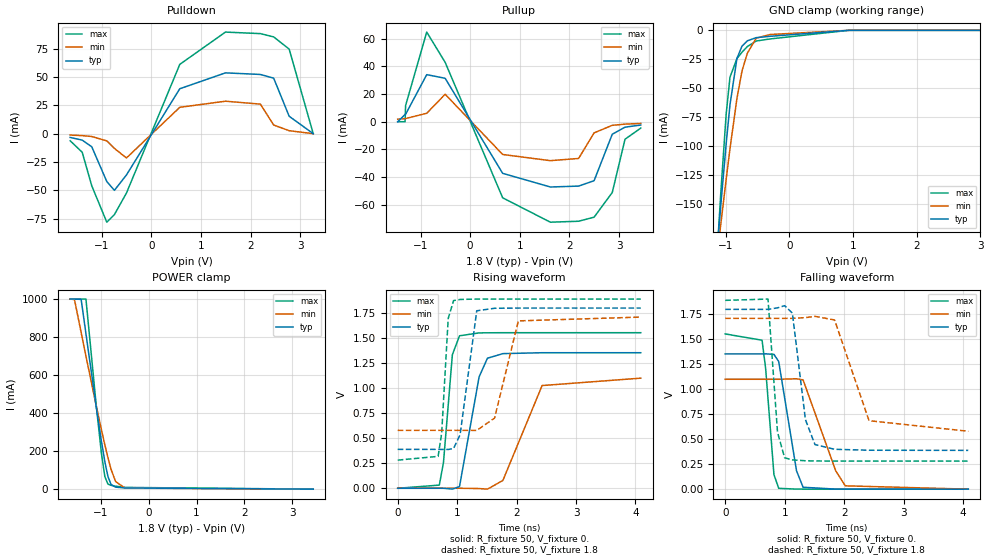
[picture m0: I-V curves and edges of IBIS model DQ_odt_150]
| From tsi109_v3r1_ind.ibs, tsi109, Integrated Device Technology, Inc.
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|   MODEL DQ_odt_150
[Model]   DQ_odt_150
Model_type  I/O
Polarity   Non-Inverting
Enable   Active-Low
|   typ   min   max
|C_comp_off 3.662p 3.671p 3.594p
|C_comp_on 3.698p 3.56p 3.948p
C_comp 3.68p 3.615p 3.771p
Cref  =   20pF
Vmeas =   0.9v
Vinl  =   0.650v
Vinh  =   1.150v
[Model Spec]
[Temperature Range]   25   125   -40
[Voltage Range] 1.8 1.71 1.89
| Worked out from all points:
|   slope of the pulldown table from 0 to 0.27 V, typ, clamps not added: 14.1 ohm
|   slope of the pullup table from 0 to 0.27 V, typ, clamps not added: 16.4 ohm
|   rising waveform, R_fixture 50, V_fixture 0.: 20-80 % time 205ps typ, 380ps min, 124ps max; typ from 0 V to 1.35 V
|   rising waveform, R_fixture 50, V_fixture 1.8: 20-80 % time 121ps typ, 188ps min, 85.6ps max; typ from 0.389 V to 1.8 V
|   falling waveform, R_fixture 50, V_fixture 0.: 20-80 % time 211ps typ, 348ps min, 119ps max; typ from 1.35 V to 0 V
|   falling waveform, R_fixture 50, V_fixture 1.8: 20-80 % time 164ps typ, 316ps min, 100ps max; typ from 1.8 V to 0.389 V
[Pulldown]
-1.636V   -3.323mA   -1.212mA   -6.26mA
-1.394V   -5.682mA   -1.723mA   -16.42mA
-1.201V   -11.61mA   -2.501mA   -46.12mA
-898.6mV  -42.29mA   -6.366mA   -78.23mA
-745.2mV  -50.07mA   -13.02mA   -71.52mA
-502.6mV  -36.5mA    -21.48mA   -52.49mA
571.6mV   39.71mA    23.3mA     61.25mA
1.492V    53.75mA    28.7mA     89.79mA
2.195V    52.34mA    26.13mA    88.44mA
2.463V    49.07mA    7.654mA    85.53mA
2.775V    15.41mA    2.629mA    74.76mA
3.26V     0A         0A         0A
[Pullup]
-1.46V    0A         1.84mA     0A
-1.311V   5.209mA    2.254mA    0A
-1.301V   5.351mA    2.288mA    11.67mA
-875.5mV  33.99mA    6.09mA     64.72mA
-504.2mV  31.36mA    19.84mA    42.89mA
654.2mV   -37.26mA   -23.65mA   -54.93mA
1.615V    -47.13mA   -28.11mA   -72.54mA
2.184V    -46.48mA   -26.52mA   -71.86mA
2.496V    -42.58mA   -8.056mA   -68.92mA
2.862V    -9.049mA   -2.593mA   -51.09mA
3.119V    -3.923mA   -1.743mA   -12.65mA
3.436V    -2.406mA   -1.258mA   -4.596mA
[GND Clamp]
-1.636V   -544mA     -441.4mA   -698.5mA
-1.119V   -177.5mA   -186.1mA   -176.8mA
-1.079V   -151.2mA   -167.4mA   -140.5mA
-994.2mV  -97.84mA   -128.5mA   -72.19mA
-934.4mV  -64.27mA   -102.2mA   -40.44mA
-824.9mV  -24.2mA    -58.74mA   -24.37mA
-745.3mV  -13.62mA   -34.97mA   -18.86mA
-660.7mV  -9.028mA   -19.65mA   -13.95mA
-521.3mV  -6.307mA   -6.754mA   -9.213mA
-307.3mV  -5.162mA   -3.62mA    -7.441mA
931.9mV   0A         0A         0A
3.26V     0A         0A         0A
[Power Clamp]
-1.636V   1A         1A         1A
-1.546V   1A         997.3mA    1A
-1.407V   998.2mA    823.6mA    1A
-1.307V   817.6mA    699.9mA    1A
-1.088V   425.2mA    433.6mA    429.7mA
-982.8mV  250.1mA    311.6mA    185.6mA
-913mV    144.8mA    233.7mA    66.39mA
-848.2mV  66.74mA    165.6mA    26.56mA
-783.3mV  24.69mA    104.6mA    20.16mA
-688.6mV  10.68mA    40.26mA    15.6mA
-494mV    6.246mA    5.746mA    9.256mA
3.436V    0A         0A         0A
[Ramp]
dV/dt_r .812/205.375p .66/380.602p .932/123.936p
dV/dt_f .847/163.938p .679/315.888p .965/99.968p
[Rising Waveform]
R_fixture = 50
V_fixture = 0.
0s        0V         0V         0V
700ps     244.5uV    -2.152uV   31.55mV
770ps     49.9uV     875.3nV    255.6mV
920ps     -8.207mV   73.82uV    1.334V
1.04ns    16.71mV    185.6uV    1.523V
1.37ns    1.113V     -2.911mV   1.552V
1.51ns    1.299V     -9.011mV   1.553V
1.77ns    1.345V     78.26mV    1.554V
2.43ns    1.354V     1.026V     1.554V
4.09ns    1.354V     1.1V       1.554V
[Rising Waveform]
R_fixture = 50
V_fixture = 1.8
V_fixture_min = 1.71
V_fixture_max = 1.89
0s        388.5mV    578.6mV    281mV
680ps     388.4mV    578.7mV    318.7mV
740ps     388mV      578.7mV    550.7mV
850ps     387.5mV    578.7mV    1.696V
940ps     397.2mV    578.7mV    1.875V
1.05ns    535.1mV    578.4mV    1.886V
1.33ns    1.773V     577.6mV    1.89V
1.63ns    1.798V     701.1mV    1.89V
2.03ns    1.8V       1.672V     1.89V
4.09ns    1.8V       1.71V      1.89V
[Falling Waveform]
R_fixture = 50
V_fixture = 0.
0s        1.354V     1.1V       1.554V
620ps     1.354V     1.1V       1.491V
680ps     1.355V     1.1V       1.208V
820ps     1.349V     1.1V       145.9mV
900ps     1.278V     1.1V       8.41mV
1.2ns     183.3mV    1.105V     710uV
1.31ns    19.37mV    1.094V     400.2uV
1.86ns    480.7uV    183.1mV    21.03uV
2.02ns    258.4uV    33.45mV    9.172uV
4.09ns    0V         23.14uV    0V
[Falling Waveform]
R_fixture = 50
V_fixture = 1.8
V_fixture_min = 1.71
V_fixture_max = 1.89
0s        1.8V       1.71V      1.89V
720ps     1.8V       1.71V      1.903V
880ps     1.815V     1.71V      568.6mV
1ns       1.837V     1.71V      313.4mV
1.13ns    1.762V     1.71V      293.2mV
1.35ns    695.3mV    1.717V     284.2mV
1.51ns    446.5mV    1.73V      282.3mV
1.84ns    399.2mV    1.694V     281.2mV
2.42ns    389.6mV    685.4mV    281mV
4.09ns    388.5mV    579.6mV    281mV
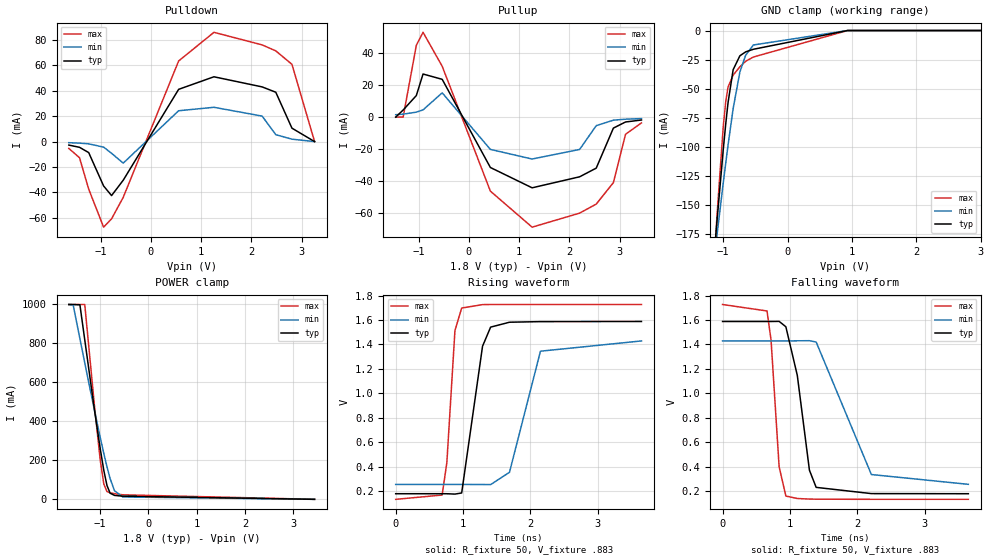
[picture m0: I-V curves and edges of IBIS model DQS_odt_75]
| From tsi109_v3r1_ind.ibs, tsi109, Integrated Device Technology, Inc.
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|   MODEL DQS_odt_75
[Model]   DQS_odt_75
Model_type  I/O
Polarity   Non-Inverting
Enable   Active-Low
|   typ   min   max
|C_comp_off 3.406p 3.404p 3.36p
|C_comp_on 3.3p 3.146p 3.514p
C_comp 3.353p 3.275p 3.437p
Cref  =   20pF
Vmeas =   0.9v
Vinl  =   0.650v
Vinh  =   1.150v
[Model Spec]
[Temperature Range]   25   125   -40
[Voltage Range] 1.8 1.71 1.89
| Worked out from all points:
|   slope of the pulldown table from 0 to 0.27 V, typ, clamps not added: 15.3 ohm
|   slope of the pullup table from 0 to 0.27 V, typ, clamps not added: 18.6 ohm
|   rising waveform, R_fixture 50, V_fixture .883: 20-80 % time 155ps typ, 260ps min, 101ps max; typ from 0.179 V to 1.59 V
|   falling waveform, R_fixture 50, V_fixture .883: 20-80 % time 210ps typ, 436ps min, 109ps max; typ from 1.59 V to 0.179 V
[Pulldown]
-1.636V   -2.749mA   -869.2uA   -5.385mA
-1.423V   -4.505mA   -1.22mA    -12.72mA
-1.24V    -8.674mA   -1.765mA   -37.45mA
-943.1mV  -34.96mA   -4.367mA   -67.46mA
-784.7mV  -42.57mA   -9.214mA   -60.9mA
-552.1mV  -30.44mA   -16.98mA   -43.96mA
551.8mV   41.2mA     24.32mA    63.56mA
1.255V    51.1mA     27.04mA    86.15mA
2.215V    43.12mA    20.1mA     76.25mA
2.487V    38.92mA    5.461mA    71.53mA
2.809V    10.58mA    1.904mA    60.92mA
3.26V     0A         0A         0A
[Pullup]
-1.46V    0A         1.493mA    0A
-1.311V   4.439mA    1.848mA    0A
-1.049V   13.48mA    3.088mA    44.96mA
-915.1mV  26.96mA    4.523mA    53.07mA
-533.9mV  23.65mA    15.18mA    31.84mA
426.4mV   -31.56mA   -20.23mA   -46.37mA
1.258V    -44.28mA   -26.26mA   -68.91mA
2.204V    -37.38mA   -20.25mA   -60.13mA
2.535V    -31.95mA   -5.371mA   -54.47mA
2.877V    -6.877mA   -1.927mA   -41.02mA
3.119V    -3.056mA   -1.316mA   -10.76mA
3.436V    -1.832mA   -944.9uA   -3.634mA
[GND Clamp]
-1.636V   -544.5mA   -441.7mA   -699.3mA
-1.118V   -178.8mA   -186.7mA   -179.7mA
-1.093V   -162.3mA   -174.9mA   -157.3mA
-998.9mV  -102.8mA   -131.4mA   -83.01mA
-959.1mV  -80.05mA   -113.8mA   -60.91mA
-924.2mV  -62.17mA   -98.82mA   -48.74mA
-844.6mV  -33.7mA    -67.13mA   -38.4mA
-740mV    -21.75mA   -35.66mA   -31.2mA
-650.4mV  -18.38mA   -21.25mA   -26.45mA
-530.9mV  -16.15mA   -12.45mA   -22.82mA
932.4mV   0A         0A         0A
3.26V     0A         0A         0A
[Power Clamp]
-1.636V   1A         1A         1A
-1.546V   1A         997.4mA    1A
-1.407V   998.4mA    824mA      1A
-1.307V   818.5mA    700.4mA    1A
-1.108V   461.3mA    458.1mA    482.6mA
-988mV    260.1mA    318.2mA    202.5mA
-913.2mV  147.7mA    234.7mA    77.91mA
-848.4mV  71mA       166.8mA    39.93mA
-783.6mV  31.4mA     106.1mA    33.6mA
-693.8mV  20.28mA    44.56mA    29.16mA
-524.3mV  16.19mA    12.26mA    23.2mA
3.436V    0A         0A         0A
[Ramp]
dV/dt_r .845/154.678p .705/260.261p .956/101.167p
dV/dt_f .845/210.589p .705/436.081p .956/108.694p
[Rising Waveform]
R_fixture = 50
V_fixture = .883
V_fixture_min = .842
V_fixture_max = .93
0s        179.2mV    255.2mV    133.3mV
690ps     179.3mV    255.2mV    168.3mV
760ps     179mV      255.2mV    435.5mV
880ps     176.2mV    255.2mV    1.514V
980ps     185.4mV    255.3mV    1.698V
1.29ns    1.386V     254.4mV    1.726V
1.41ns    1.542V     253.8mV    1.727V
1.69ns    1.582V     354.6mV    1.727V
2.15ns    1.587V     1.345V     1.727V
3.65ns    1.588V     1.429V     1.727V
[Falling Waveform]
R_fixture = 50
V_fixture = .883
V_fixture_min = .842
V_fixture_max = .93
0s        1.588V     1.429V     1.727V
660ps     1.588V     1.429V     1.674V
720ps     1.588V     1.429V     1.437V
840ps     1.589V     1.429V     399.9mV
940ps     1.545V     1.429V     160.3mV
1.11ns    1.147V     1.43V      140mV
1.29ns    371.6mV    1.431V     135.5mV
1.39ns    231.1mV    1.42V      134.5mV
2.21ns    180.2mV    336.1mV    133.3mV
3.65ns    179.2mV    256.1mV    133.3mV
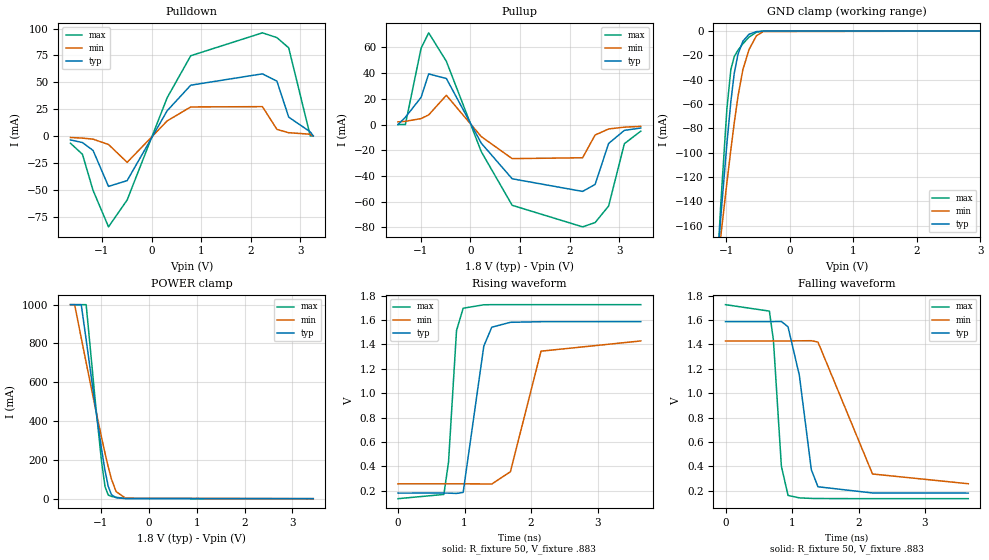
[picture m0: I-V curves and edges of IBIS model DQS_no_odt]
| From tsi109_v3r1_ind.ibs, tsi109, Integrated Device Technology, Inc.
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|   MODEL DQS_no_odt
[Model]   DQS_no_odt
Model_type  I/O
Polarity   Non-Inverting
Enable   Active-Low
|   typ   min   max
|C_comp_off 3.963p 3.979p 3.887p
|C_comp_on 3.3p 3.146p 3.514p
C_comp 3.631p 3.563p 3.7p
Cref  =   20pF
Vmeas =   0.9v
Vinl  =   0.650v
Vinh  =   1.150v
[Model Spec]
[Temperature Range]   25   125   -40
[Voltage Range] 1.8 1.71 1.89
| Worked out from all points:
|   slope of the pulldown table from 0 to 0.27 V, typ, clamps not added: 13.2 ohm
|   slope of the pullup table from 0 to 0.27 V, typ, clamps not added: 15.5 ohm
|   GND clamp passes 1 mA (typ) near -0.57 V on its own axis
|   POWER clamp passes 1 mA (typ) near -0.54 V on its own axis
|   rising waveform, R_fixture 50, V_fixture .883: 20-80 % time 155ps typ, 260ps min, 101ps max; typ from 0.179 V to 1.59 V
|   falling waveform, R_fixture 50, V_fixture .883: 20-80 % time 210ps typ, 436ps min, 109ps max; typ from 1.59 V to 0.179 V
[Pulldown]
-1.636V   -3.649mA   -1.42mA    -6.738mA
-1.394V   -6.111mA   -1.982mA   -17.07mA
-1.181V   -13.42mA   -2.956mA   -50.56mA
-868.9mV  -46.94mA   -7.907mA   -84.6mA
-492.7mV  -41.54mA   -24.55mA   -59.58mA
314.2mV   23.5mA     14.07mA    35.62mA
789.4mV   47.29mA    27.03mA    74.71mA
2.235V    57.86mA    27.32mA    96.04mA
2.527V    51.06mA    6.183mA    91.58mA
2.765V    17.53mA    3.042mA    82.06mA
3.2V      3.847mA    1.638mA    0A
3.26V     0A         0A         0A
[Pullup]
-1.46V    0A         2.056mA    0A
-1.311V   5.643mA    2.505mA    0A
-994.3mV  21.14mA    4.624mA    59.29mA
-840.9mV  39.38mA    7.502mA    71.33mA
-484.4mV  35.79mA    22.74mA    49.19mA
218.5mV   -14.46mA   -9.366mA   -21.02mA
842.3mV   -42.19mA   -26.52mA   -62.82mA
2.263V    -52.03mA   -25.85mA   -79.59mA
2.515V    -46.59mA   -8.159mA   -76.27mA
2.788V    -14.69mA   -3.435mA   -63.37mA
3.105V    -4.545mA   -2.034mA   -14.9mA
3.436V    -2.732mA   -1.461mA   -5.145mA
[GND Clamp]
-1.636V   -543.7mA   -441.2mA   -698mA
-1.118V   -176.6mA   -185.6mA   -174.9mA
-1.08V    -150.9mA   -167.3mA   -139.4mA
-987.6mV  -92.79mA   -125mA     -64.17mA
-924.6mV  -57.85mA   -97.43mA   -31.52mA
-871.4mV  -34.73mA   -75.48mA   -21.01mA
-813.3mV  -19.18mA   -53.93mA   -15.8mA
-735.9mV  -8.366mA   -31.74mA   -10.49mA
-639mV    -2.666mA   -15.21mA   -4.969mA
-522.9mV  -456.8uA   -3.897mA   -972.8uA
-416.4mV  -69.24uA   -425.6uA   -102.1uA
3.26V     0A         0A         0A
[Power Clamp]
-1.636V   1A         1A         1A
-1.549V   1A         1A         1A
-1.411V   1A         828.4mA    1A
-1.308V   819.5mA    701.2mA    1A
-1.114V   469.8mA    464.3mA    493.8mA
-985.5mV  253.4mA    314.2mA    188.6mA
-913.7mV  144.6mA    234mA      62.25mA
-847.1mV  63.87mA    164mA      18.73mA
-780.5mV  20.7mA     101.5mA    11.83mA
-683.2mV  5.068mA    36.78mA    7.26mA
-483.3mV  394.4uA    2.059mA    974.7uA
3.436V    0A         0A         0A
[Ramp]
dV/dt_r .845/154.678p .705/260.261p .956/101.167p
dV/dt_f .845/210.589p .705/436.081p .956/108.694p
[Rising Waveform]
R_fixture = 50
V_fixture = .883
V_fixture_min = .842
V_fixture_max = .93
0s        179.2mV    255.2mV    133.3mV
690ps     179.3mV    255.2mV    168.3mV
760ps     179mV      255.2mV    435.5mV
880ps     176.2mV    255.2mV    1.514V
980ps     185.4mV    255.3mV    1.698V
1.29ns    1.386V     254.4mV    1.726V
1.41ns    1.542V     253.8mV    1.727V
1.69ns    1.582V     354.6mV    1.727V
2.15ns    1.587V     1.345V     1.727V
3.65ns    1.588V     1.429V     1.727V
[Falling Waveform]
R_fixture = 50
V_fixture = .883
V_fixture_min = .842
V_fixture_max = .93
0s        1.588V     1.429V     1.727V
660ps     1.588V     1.429V     1.674V
720ps     1.588V     1.429V     1.437V
840ps     1.589V     1.429V     399.9mV
940ps     1.545V     1.429V     160.3mV
1.11ns    1.147V     1.43V      140mV
1.29ns    371.6mV    1.431V     135.5mV
1.39ns    231.1mV    1.42V      134.5mV
2.21ns    180.2mV    336.1mV    133.3mV
3.65ns    179.2mV    256.1mV    133.3mV
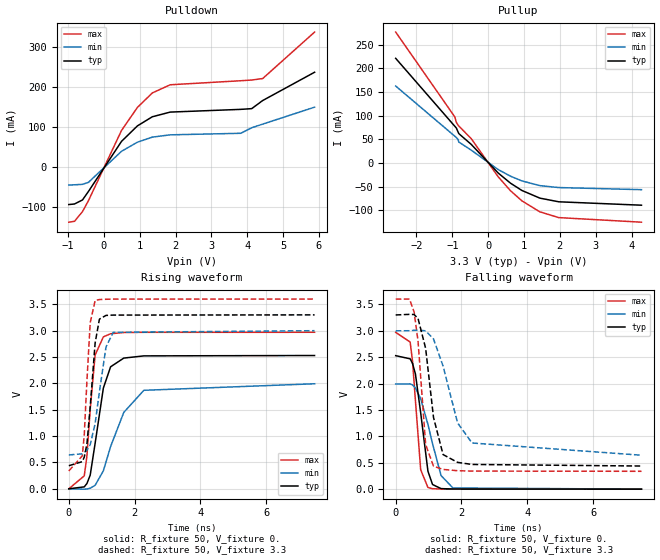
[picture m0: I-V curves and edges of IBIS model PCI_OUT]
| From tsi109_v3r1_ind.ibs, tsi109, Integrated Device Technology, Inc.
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|   MODEL PCI_OUT
[Model]   PCI_OUT
Model_type  Output
C_comp 4.536p 4.202p 4.874p
Polarity   Non-Inverting
Enable   Active-High
Vmeas =   1.50V
Cref =   10pF
Rref =   50
Vref=   0.0V
[Temperature Range]   27.0   125.0   -40.0
[POWER Clamp Reference]   3.30V   3.00V   3.60V
[GND Clamp Reference]   0.00V   0.00V   0.00V
[Voltage Range] 3.3 3. 3.6
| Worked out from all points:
|   slope of the pulldown table from 0 to 0.495 V, typ, clamps not added: 7.81 ohm
|   slope of the pullup table from 0 to 0.495 V, typ, clamps not added: 13.9 ohm
|   rising waveform, R_fixture 50, V_fixture 0.: 20-80 % time 365ps typ, 723ps min, 222ps max; typ from 0 V to 2.53 V
|   rising waveform, R_fixture 50, V_fixture 3.3: 20-80 % time 214ps typ, 317ps min, 159ps max; typ from 0.438 V to 3.3 V
|   falling waveform, R_fixture 50, V_fixture 0.: 20-80 % time 295ps typ, 484ps min, 203ps max; typ from 2.53 V to 0 V
|   falling waveform, R_fixture 50, V_fixture 3.3: 20-80 % time 338ps typ, 623ps min, 226ps max; typ from 3.3 V to 0.438 V
[Pulldown]
-976.9mV  -94.66mA   -46.06mA   -138.7mA
-817.5mV  -93.23mA   -45.29mA   -136.5mA
-595.7mV  -83.14mA   -44.21mA   -112.2mA
-429.3mV  -61.97mA   -39.17mA   -84.92mA
492.7mV   63.11mA    38.33mA    90.31mA
936.3mV   101.8mA    61.1mA     147.9mA
1.352V    124.6mA    73.73mA    184.1mA
1.851V    136.3mA    79.48mA    204.5mA
3.82V     143.1mA    83.35mA    214.6mA
4.125V    144.9mA    97.25mA    216.4mA
4.43V     165.1mA    106.2mA    220mA
5.879V    235.8mA    148.6mA    336.1mA
[Pullup]
-2.579V   220.8mA    162.3mA    276.3mA
-929mV    77.21mA    56.24mA    96.97mA
-887.4mV  73.58mA    53.57mA    85.73mA
-838.9mV  65.18mA    49.35mA    79.56mA
-818.1mV  61.78mA    43.99mA    77.84mA
-471.5mV  38.99mA    26.83mA    51.07mA
277.2mV   -21.28mA   -14.01mA   -29.14mA
623.8mV   -42.97mA   -28.22mA   -58.92mA
942.6mV   -58.4mA    -38.19mA   -80.33mA
1.442V    -74.52mA   -48.11mA   -103.5mA
1.969V    -82.31mA   -52.22mA   -115.7mA
4.277V    -89.5mA    -56.68mA   -125.4mA
[Ramp]
dV/dt_r 1.518/365.23p 1.196/721.023p 1.782/221.8p
dV/dt_f 1.717/337.435p 1.415/622.991p 1.957/226.082p
[Rising Waveform]
R_fixture = 50
V_fixture = 0.
0s        0V         0V         0V
470ps     37.05mV    -6.726mV   246.6mV
550ps     99.96mV    -3.323mV   620.7mV
650ps     259.3mV    11.36mV    1.507V
800ps     863.9mV    67.25mV    2.539V
1.05ns    1.912V     341.7mV    2.883V
1.27ns    2.315V     802.2mV    2.942V
1.67ns    2.48V      1.449V     2.965V
2.28ns    2.522V     1.869V     2.969V
7.47ns    2.529V     1.993V     2.97V
[Rising Waveform]
R_fixture = 50
V_fixture = 3.3
V_fixture_min = 3.
V_fixture_max = 3.6
0s        438.2mV    642.1mV    338.6mV
410ps     515.4mV    664.5mV    626mV
470ps     601.9mV    685.9mV    1.029V
550ps     848.7mV    731.3mV    2.042V
650ps     1.557V     836.6mV    3.151V
800ps     2.767V     1.238V     3.573V
930ps     3.219V     1.841V     3.591V
1.13ns    3.29V      2.691V     3.596V
1.35ns    3.296V     2.969V     3.599V
7.47ns    3.3V       3V         3.6V
[Falling Waveform]
R_fixture = 50
V_fixture = 0.
0s        2.529V     1.993V     2.97V
440ps     2.469V     1.994V     2.787V
510ps     2.384V     1.976V     2.438V
600ps     2.182V     1.917V     1.677V
760ps     1.445V     1.712V     366.7mV
980ps     340.4mV    1.227V     32.06mV
1.12ns    87.95mV    862.5mV    8.858mV
1.38ns    10.32mV    256.9mV    3.596mV
1.74ns    3.211mV    22.96mV    1.388mV
7.47ns    1.068uV    15.07uV    0V
[Falling Waveform]
R_fixture = 50
V_fixture = 3.3
V_fixture_min = 3.
V_fixture_max = 3.6
0s        3.3V       3V         3.6V
420ps     3.311V     3.001V     3.601V
560ps     3.308V     3.009V     3.356V
680ps     3.232V     3.01V      2.799V
910ps     2.668V     3V         845.2mV
1.15ns    1.357V     2.845V     435.1mV
1.44ns    655.6mV    2.332V     374.1mV
1.88ns    507.9mV    1.256V     349.5mV
2.32ns    467.9mV    874.5mV    342.5mV
7.47ns    438.2mV    643.1mV    338.6mV
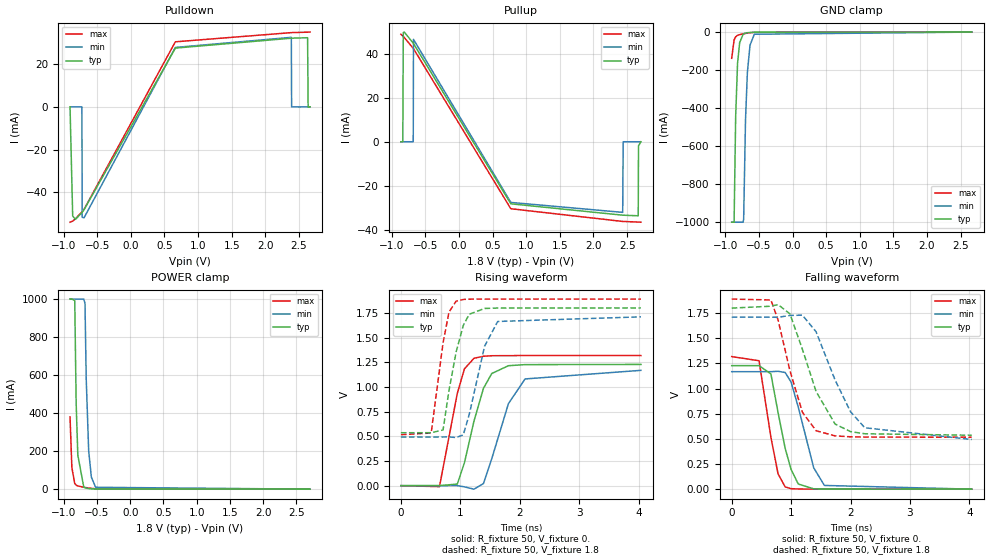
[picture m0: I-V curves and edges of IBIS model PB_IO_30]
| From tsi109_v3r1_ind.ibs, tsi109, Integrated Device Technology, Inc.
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|   MODEL PB_IO_30
[Model]   PB_IO_30
Model_type  I/O
Polarity   Non-Inverting
Enable   Active-High
|   typ   min   max
|C_comp_off 3.714p 3.449p 3.979p
|C_comp_on 4.306p 3.81p 4.757p
C_comp 4.01p 3.63p 4.368p
Vinl  =   0.300v
Vinh  =   1.500v
Vmeas =   0.9000V
Cref  =   1.0pF
Rref  =   50.0000
Vref  =   0.0V
[Model Spec]
[Temperature Range]   25   125   -40
[Voltage Range] 1.8 1.71 1.89
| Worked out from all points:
|   slope of the pulldown table from 0 to 0.27 V, typ, clamps not added: 16.6 ohm
|   slope of the pullup table from 0 to 0.27 V, typ, clamps not added: 18.8 ohm
|   GND clamp passes 1 mA (typ) near -0.59 V on its own axis
|   POWER clamp passes 1 mA (typ) near -0.54 V on its own axis
|   rising waveform, R_fixture 50, V_fixture 0.: 20-80 % time 312ps typ, 380ps min, 232ps max; typ from 0 V to 1.23 V
|   rising waveform, R_fixture 50, V_fixture 1.8: 20-80 % time 240ps typ, 282ps min, 190ps max; typ from 0.536 V to 1.8 V
|   falling waveform, R_fixture 50, V_fixture 0.: 20-80 % time 255ps typ, 300ps min, 205ps max; typ from 1.23 V to 0 V
|   falling waveform, R_fixture 50, V_fixture 1.8: 20-80 % time 451ps typ, 545ps min, 363ps max; typ from 1.8 V to 0.536 V
[Pulldown]
-905.9mV  0A         0A         -53.93mA
-866.2mV  -51.03mA   0A         -53.42mA
-826.5mV  -52.6mA    0A         -52.37mA
-728.9mV  -49.53mA   0A         -49.13mA
-725.3mV  -49.37mA   -51.66mA   -48.99mA
-696.4mV  -48.04mA   -51.83mA   -47.86mA
661.7mV   27.52mA    27.83mA    30.46mA
2.388V    32.15mA    32.55mA    34.76mA
2.392V    32.16mA    0A         34.77mA
2.63V     32.37mA    0A         34.97mA
2.638V    0A         0A         34.98mA
2.667V    0A         0A         35.01mA
[Pullup]
-866.5mV  0A         0A         48.72mA
-837.6mV  0A         0A         47.94mA
-830.4mV  49.49mA    0A         47.72mA
-815.9mV  49.71mA    0A         47.26mA
-682.3mV  44.71mA    0A         42.34mA
-678.7mV  44.53mA    46.42mA    42.2mA
769.8mV   -28.13mA   -27.5mA    -30.36mA
2.435V    -33.28mA   -32.01mA   -36.12mA
2.442V    -33.29mA   0A         -36.13mA
2.666V    -33.56mA   0A         -36.41mA
2.67V     -1.866mA   0A         -36.41mA
2.706V    0A         0A         -36.46mA
[GND Clamp]
-905.9mV  -1A        -1A        -137.9mA
-870.3mV  -1A        -1A        -41.43mA
-846.6mV  -441.9mA   -1A        -24.54mA
-818.8mV  -164.5mA   -1A        -17.08mA
-787.2mV  -54.7mA    -1A        -13.21mA
-735.7mV  -11.66mA   -1A        -9.248mA
-727.8mV  -9.573mA   -983.7mA   -8.719mA
-700.1mV  -5.335mA   -460.2mA   -6.983mA
-672.3mV  -3.348mA   -211.4mA   -5.421mA
-632.8mV  -1.857mA   -68.65mA   -3.514mA
-569.4mV  -685.4uA   -11.35mA   -1.391mA
2.667V    0A         0A         0A
[Power Clamp]
-905.9mV  1A         1A         380.5mA
-878.2mV  1A         1A         113.3mA
-835mV    992.8mA    1A         29.9mA
-813.4mV  448.2mA    1A         21.21mA
-788.7mV  179.3mA    1A         16.86mA
-699.3mV  10.92mA    1A         10.05mA
-680.8mV  7.495mA    977.8mA    8.969mA
-662.3mV  5.499mA    579.6mA    7.938mA
-625.2mV  3.317mA    200.9mA    6.022mA
-585.1mV  1.988mA    63.4mA     4.19mA
-520.4mV  744.8uA    9.906mA    1.885mA
2.706V    0A         0A         0A
[Ramp]
dV/dt_r .737/312.486p .701/380.002p .791/232.014p
dV/dt_f .758/450.715p .73/545.704p .824/362.761p
[Rising Waveform]
R_fixture = 50
V_fixture = 0.
0s        0V         0V         0V
650ps     555.7uV    -23.99uV   -9.787mV
950ps     16.08mV    470uV      934.5mV
1.07ns    232.3mV    -11.99mV   1.183V
1.23ns    652.4mV    -35.49mV   1.29V
1.39ns    985.6mV    21.28mV    1.311V
1.53ns    1.136V     273.6mV    1.316V
1.81ns    1.215V     830mV      1.317V
2.09ns    1.226V     1.081V     1.318V
4.04ns    1.228V     1.168V     1.318V
[Rising Waveform]
R_fixture = 50
V_fixture = 1.8
V_fixture_min = 1.71
V_fixture_max = 1.89
0s        536.1mV    492.7mV    516.3mV
510ps     536.3mV    492.7mV    533.1mV
710ps     564.5mV    493mV      1.446V
810ps     965.1mV    493.8mV    1.758V
930ps     1.354V     487.5mV    1.869V
1.05ns    1.622V     513.9mV    1.886V
1.15ns    1.736V     719.1mV    1.889V
1.41ns    1.795V     1.414V     1.89V
1.63ns    1.799V     1.663V     1.89V
4.04ns    1.8V       1.71V      1.89V
[Falling Waveform]
R_fixture = 50
V_fixture = 0.
0s        1.228V     1.168V     1.318V
460ps     1.228V     1.168V     1.277V
660ps     1.146V     1.168V     516.3mV
780ps     762.9mV    1.172V     152.7mV
900ps     405.5mV    1.16V      22.2mV
1ns       195.5mV    1.064V     4.98mV
1.12ns    51.47mV    817mV      1.946mV
1.38ns    3.13mV     212.7mV    558.5uV
1.56ns    1.376mV    37.03mV    240.4uV
4.04ns    0V         9.409uV    0V
[Falling Waveform]
R_fixture = 50
V_fixture = 1.8
V_fixture_min = 1.71
V_fixture_max = 1.89
0s        1.8V       1.71V      1.89V
660ps     1.819V     1.71V      1.881V
780ps     1.835V     1.709V     1.683V
980ps     1.743V     1.727V     1.178V
1.19ns    1.391V     1.73V      765mV
1.42ns    971.5mV    1.565V     580.9mV
1.74ns    647.4mV    1.085V     529.7mV
2ns       572.1mV    769.5mV    520.6mV
2.24ns    550.8mV    610.5mV    517.9mV
4.04ns    536.1mV    493.7mV    516.3mV
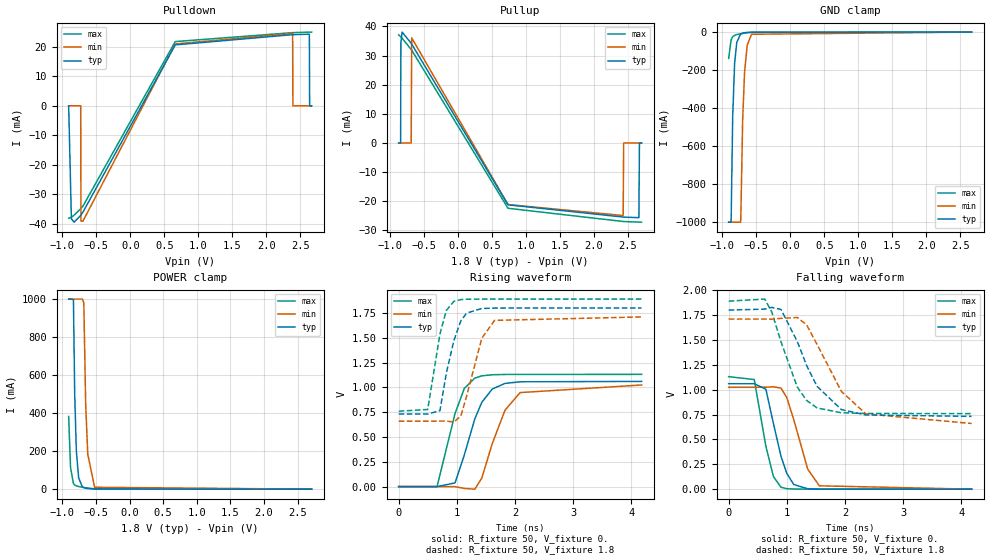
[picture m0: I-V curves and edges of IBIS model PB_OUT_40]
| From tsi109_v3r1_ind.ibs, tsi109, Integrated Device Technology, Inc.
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[Model]   PB_OUT_40
Model_type  Output
Polarity   Non-Inverting
Enable   Active-High
|   typ   min   max
|C_comp_off 3.714p 3.449p 3.979p
|C_comp_on 4.164p 3.713p 4.513p
C_comp 3.939p 3.581p 4.246p
Vinl  =   0.300v
Vinh  =   1.500v
Vmeas =   0.9000V
Cref  =   1.0pF
Rref  =   50.0000
Vref  =   0.0V
[Model Spec]
[Temperature Range]   25   125   -40
[Voltage Range] 1.8 1.71 1.89
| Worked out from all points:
|   slope of the pulldown table from 0 to 0.27 V, typ, clamps not added: 22.1 ohm
|   slope of the pullup table from 0 to 0.27 V, typ, clamps not added: 24.6 ohm
|   GND clamp passes 1 mA (typ) near -0.59 V on its own axis
|   POWER clamp passes 1 mA (typ) near -0.54 V on its own axis
|   rising waveform, R_fixture 50, V_fixture 0.: 20-80 % time 351ps typ, 382ps min, 277ps max; typ from 0 V to 1.06 V
|   rising waveform, R_fixture 50, V_fixture 1.8: 20-80 % time 243ps typ, 281ps min, 201ps max; typ from 0.732 V to 1.8 V
|   falling waveform, R_fixture 50, V_fixture 0.: 20-80 % time 258ps typ, 298ps min, 210ps max; typ from 1.06 V to 0 V
|   falling waveform, R_fixture 50, V_fixture 1.8: 20-80 % time 512ps typ, 613ps min, 411ps max; typ from 1.8 V to 0.732 V
[Pulldown]
-906mV    0A         0A         -38.11mA
-866.3mV  -38.27mA   0A         -37.78mA
-826.6mV  -39.45mA   0A         -37.08mA
-729mV    -37.15mA   0A         -34.88mA
-725.4mV  -37.03mA   -39.06mA   -34.78mA
-696.5mV  -36.04mA   -39.11mA   -34.01mA
661.7mV   20.65mA    20.97mA    21.77mA
2.388V    24.12mA    24.53mA    24.8mA
2.392V    24.12mA    0A         24.81mA
2.634V    24.29mA    0A         24.97mA
2.638V    0A         0A         24.97mA
2.667V    0A         0A         24.99mA
[Pullup]
-866.6mV  0A         0A         37.11mA
-837.7mV  0A         0A         36.49mA
-834.1mV  34.47mA    0A         36.41mA
-816mV    38.07mA    0A         35.96mA
-682.3mV  34.23mA    0A         32.11mA
-675.1mV  33.95mA    36.08mA    31.87mA
740.9mV   -21.2mA    -21.1mA    -22.38mA
2.435V    -25.4mA    -24.88mA   -26.92mA
2.442V    -25.41mA   0A         -26.93mA
2.666V    -25.61mA   0A         -27.12mA
2.674V    0A         0A         -27.13mA
2.706V    0A         0A         -27.16mA
[GND Clamp]
-906mV    -1A        -1A        -138.5mA
-870.4mV  -1A        -1A        -41.43mA
-846.7mV  -443.6mA   -1A        -24.48mA
-818.9mV  -165.1mA   -1A        -17.07mA
-787.3mV  -54.66mA   -1A        -13.23mA
-731.8mV  -10.57mA   -1A        -8.987mA
-727.9mV  -9.631mA   -986.9mA   -8.726mA
-700.2mV  -5.362mA   -461.4mA   -6.989mA
-672.4mV  -3.349mA   -211.8mA   -5.424mA
-632.8mV  -1.859mA   -68.73mA   -3.516mA
-569.5mV  -686.7uA   -11.4mA    -1.394mA
2.667V    0A         0A         0A
[Power Clamp]
-906mV    1A         1A         382.4mA
-878.3mV  1A         1A         113.9mA
-835.1mV  996.9mA    1A         29.8mA
-816.6mV  504.7mA    1A         22.03mA
-791.9mV  201.6mA    1A         17.28mA
-758mV    59.94mA    1A         13.94mA
-702.4mV  11.79mA    1A         10.24mA
-680.9mV  7.51mA     979.8mA    8.974mA
-653.1mV  4.793mA    446.3mA    7.444mA
-622.2mV  3.19mA     184.3mA    5.874mA
-520.4mV  746.2uA    9.952mA    1.888mA
2.706V    0A         0A         0A
[Ramp]
dV/dt_r .636/350.688p .615/382.229p .679/277.286p
dV/dt_f .641/511.996p .631/613.561p .678/411.365p
[Rising Waveform]
R_fixture = 50
V_fixture = 0.
0s        0V         0V         0V
660ps     -377uV     -33.31uV   -835.1uV
970ps     37.1mV     -811.8uV   736.8mV
1.13ns    319.3mV    -18.86mV   989.8mV
1.31ns    682.1mV    -26.17mV   1.093V
1.43ns    848.8mV    84.6mV     1.116V
1.61ns    982.8mV    432.7mV    1.127V
1.83ns    1.04V      770.5mV    1.13V
2.09ns    1.056V     947.3mV    1.13V
4.18ns    1.06V      1.024V     1.131V
[Rising Waveform]
R_fixture = 50
V_fixture = 1.8
V_fixture_min = 1.71
V_fixture_max = 1.89
0s        731.7mV    659.2mV    759.6mV
500ps     731.9mV    659.2mV    777.1mV
710ps     764.9mV    659.6mV    1.538V
820ps     1.143V     660mV      1.775V
950ps     1.472V     651mV      1.867V
1.07ns    1.671V     710.7mV    1.885V
1.17ns    1.749V     913.8mV    1.888V
1.43ns    1.795V     1.495V     1.89V
1.65ns    1.799V     1.675V     1.89V
4.18ns    1.8V       1.71V      1.89V
[Falling Waveform]
R_fixture = 50
V_fixture = 0.
0s        1.06V      1.024V     1.131V
440ps     1.06V      1.024V     1.102V
640ps     1.005V     1.025V     432.1mV
770ps     660.6mV    1.029V     127.3mV
900ps     330.9mV    1.016V     19.31mV
1ns       158.6mV    920.8mV    4.531mV
1.12ns    46.82mV    698.4mV    1.475mV
1.36ns    3.689mV    201.6mV    384.1uV
1.56ns    1.25mV     33.8mV     130.8uV
4.18ns    0V         8.143uV    0V
[Falling Waveform]
R_fixture = 50
V_fixture = 1.8
V_fixture_min = 1.71
V_fixture_max = 1.89
0s        1.8V       1.71V      1.89V
620ps     1.81V      1.71V      1.911V
740ps     1.827V     1.709V     1.784V
900ps     1.807V     1.717V     1.482V
1.18ns    1.485V     1.726V     1.027V
1.34ns    1.246V     1.653V     892.5mV
1.52ns    1.034V     1.456V     816.8mV
1.94ns    799.9mV    982.5mV    767.9mV
2.36ns    746.1mV    756.9mV    760.9mV
4.18ns    731.7mV    660.1mV    759.6mV
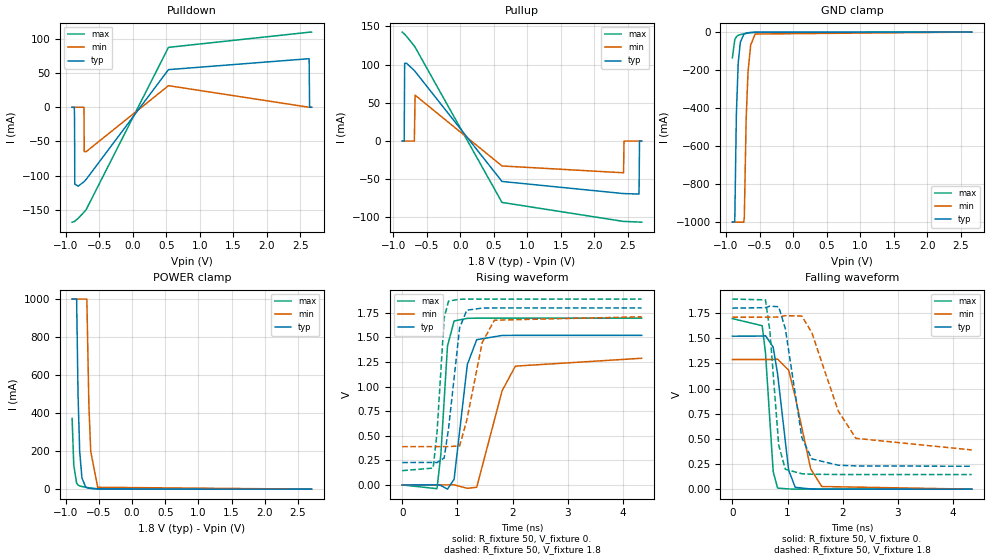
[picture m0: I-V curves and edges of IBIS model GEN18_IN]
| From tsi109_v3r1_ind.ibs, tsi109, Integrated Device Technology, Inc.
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[Model]   GEN18_IN
Model_type  Input
Polarity   Non-Inverting
Enable   Active-High
|   typ   min   max
|C_comp_off 3.714p 3.449p 3.979p
|C_comp_on 4.671p 4.263p 5.086p
C_comp 4.192p 3.856p 4.532p
Vinl  =   0.300v
Vinh  =   1.500v
Vmeas =   0.9000V
Cref  =   1.0pF
Rref  =   50.0000
Vref  =   0.0V
[Model Spec]
[Temperature Range]   25   125   -40
[Voltage Range] 1.8 1.71 1.89
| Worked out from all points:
|   slope of the pulldown table from 0 to 0.27 V, typ, clamps not added: 7.56 ohm
|   slope of the pullup table from 0 to 0.27 V, typ, clamps not added: 9.12 ohm
|   GND clamp passes 1 mA (typ) near -0.59 V on its own axis
|   POWER clamp passes 1 mA (typ) near -0.54 V on its own axis
|   rising waveform, R_fixture 50, V_fixture 0.: 20-80 % time 178ps typ, 338ps min, 109ps max; typ from 0 V to 1.52 V
|   rising waveform, R_fixture 50, V_fixture 1.8: 20-80 % time 179ps typ, 281ps min, 111ps max; typ from 0.228 V to 1.8 V
|   falling waveform, R_fixture 50, V_fixture 0.: 20-80 % time 187ps typ, 296ps min, 116ps max; typ from 1.52 V to 0 V
|   falling waveform, R_fixture 50, V_fixture 1.8: 20-80 % time 255ps typ, 510ps min, 145ps max; typ from 1.8 V to 0.228 V
[Pulldown]
-905.5mV  0A         0A         -168.3mA
-873mV    0A         0A         -167.3mA
-869.3mV  -15.33mA   0A         -167mA
-865.7mV  -112.5mA   0A         -166.8mA
-815.2mV  -115.6mA   0A         -162.6mA
-728.5mV  -109mA     0A         -153.7mA
-724.9mV  -108.6mA   -64.94mA   -153.3mA
-696mV    -105.6mA   -65mA      -149.9mA
531.9mV   55.13mA    31.64mA    87.73mA
2.63V     71.14mA    0A         109.9mA
2.637V    0A         0A         110mA
2.666V    0A         0A         110.1mA
[Pullup]
-866.2mV  0A         0A         142.6mA
-837.3mV  0A         0A         140.3mA
-830.1mV  101.7mA    0A         139.7mA
-801.2mV  101.8mA    0A         136.9mA
-685.7mV  92.24mA    0A         124.3mA
-674.8mV  91.13mA    60.07mA    122.9mA
621.7mV   -52.88mA   -32.62mA   -80.33mA
2.435V    -68.76mA   -41.53mA   -105.2mA
2.442V    -68.78mA   0A         -105.2mA
2.666V    -69.35mA   0A         -106mA
2.673V    0A         0A         -106.1mA
2.705V    0A         0A         -106.2mA
[GND Clamp]
-905.5mV  -1A        -1A        -135.4mA
-869.8mV  -997.8mA   -1A        -40.78mA
-846.1mV  -434.7mA   -1A        -24.25mA
-818.4mV  -161.8mA   -1A        -16.97mA
-786.7mV  -53.78mA   -1A        -13.18mA
-735.3mV  -11.55mA   -1A        -9.218mA
-727.3mV  -9.494mA   -973.7mA   -8.691mA
-699.6mV  -5.303mA   -454.7mA   -6.959mA
-671.9mV  -3.32mA    -208.8mA   -5.397mA
-632.3mV  -1.845mA   -67.93mA   -3.496mA
-565.1mV  -634.9uA   -10.08mA   -1.288mA
2.666V    0A         0A         0A
[Power Clamp]
-905.5mV  1A         1A         372.3mA
-880.8mV  1A         1A         126.4mA
-837.6mV  1A         1A         31.59mA
-816mV    494.2mA    1A         21.92mA
-791.4mV  197.7mA    1A         17.19mA
-757.4mV  58.87mA    1A         13.9mA
-701.9mV  11.65mA    1A         10.21mA
-683.4mV  7.9mA      1A         9.121mA
-652.6mV  4.758mA    440.2mA    7.418mA
-624.8mV  3.297mA    198.7mA    6.001mA
-520mV    740.6uA    9.847mA    1.874mA
2.705V    0A         0A         0A
[Ramp]
dV/dt_r .913/177.771p .773/338.311p 1.018/108.877p
dV/dt_f .943/254.559p .793/510.536p 1.047/145.208p
[Rising Waveform]
R_fixture = 50
V_fixture = 0.
0s        0V         0V         0V
630ps     1.026mV    -11.3uV    -38.16mV
700ps     -5.507mV   -139.2uV   311mV
820ps     -43.09mV   483.7uV    1.412V
940ps     57.21mV    823.1uV    1.667V
1.18ns    1.225V     -34.59mV   1.694V
1.35ns    1.477V     -23.74mV   1.696V
1.81ns    1.52V      956.8mV    1.696V
2.05ns    1.521V     1.208V     1.696V
4.34ns    1.521V     1.288V     1.696V
[Rising Waveform]
R_fixture = 50
V_fixture = 1.8
V_fixture_min = 1.71
V_fixture_max = 1.89
0s        227.8mV    389.2mV    145.4mV
560ps     228.5mV    389.2mV    171.1mV
630ps     227.7mV    389.2mV    528.7mV
760ps     273.7mV    389.9mV    1.701V
840ps     576.4mV    390.1mV    1.87V
1.04ns    1.597V     396.1mV    1.888V
1.17ns    1.777V     658.9mV    1.89V
1.45ns    1.798V     1.448V     1.89V
1.67ns    1.8V       1.675V     1.89V
4.34ns    1.8V       1.71V      1.89V
[Falling Waveform]
R_fixture = 50
V_fixture = 0.
0s        1.521V     1.289V     1.696V
540ps     1.522V     1.289V     1.625V
600ps     1.526V     1.289V     1.357V
740ps     1.411V     1.289V     174.2mV
820ps     1.145V     1.293V     10.89mV
1.02ns    188.8mV    1.183V     2.031mV
1.14ns    18.25mV    915.9mV    1.027mV
1.42ns    2.208mV    201.7mV    230.8uV
1.62ns    993.3uV    26.39mV    82.63uV
4.34ns    0V         13.39uV    0V
[Falling Waveform]
R_fixture = 50
V_fixture = 1.8
V_fixture_min = 1.71
V_fixture_max = 1.89
0s        1.8V       1.71V      1.89V
600ps     1.804V     1.71V      1.882V
680ps     1.82V      1.71V      1.573V
840ps     1.813V     1.712V     437.8mV
960ps     1.596V     1.725V     197.7mV
1.26ns    511.6mV    1.721V     153.4mV
1.44ns    300.7mV    1.556V     148.4mV
1.92ns    238mV      776.1mV    145.7mV
2.24ns    231.1mV    505.4mV    145.5mV
4.34ns    227.8mV    390.2mV    145.4mV
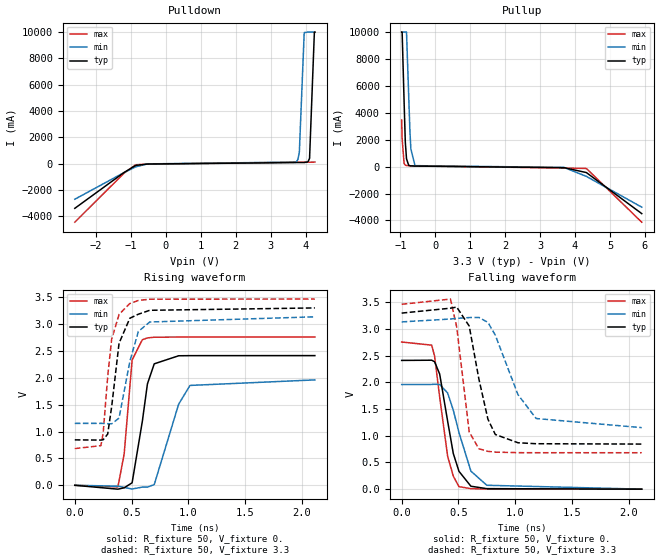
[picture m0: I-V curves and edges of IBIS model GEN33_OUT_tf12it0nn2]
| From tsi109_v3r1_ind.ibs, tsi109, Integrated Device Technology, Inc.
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|   MODEL GEN33_OUT_tf12it0nn2
[Model]   GEN33_OUT_tf12it0nn2
Model_type  Output
C_comp 1.766p 1.721p 1.803p
Polarity   Non-Inverting
Enable   Active-High
Vmeas =   1.65V
|   typ   min   max
[Model Spec]
[Temperature Range]   25   125   -40
[Voltage Range] 3.3 3.135 3.465
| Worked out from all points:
|   slope of the pulldown table from 0 to 0.495 V, typ, clamps not added: 15.3 ohm
|   slope of the pullup table from 0 to 0.495 V, typ, clamps not added: 16.3 ohm
|   rising waveform, R_fixture 50, V_fixture 0.: 20-80 % time 92.1ps typ, 147ps min, 63.9ps max; typ from 0 V to 2.41 V
|   rising waveform, R_fixture 50, V_fixture 3.3: 20-80 % time 90.2ps typ, 107ps min, 82.4ps max; typ from 0.845 V to 3.3 V
|   falling waveform, R_fixture 50, V_fixture 0.: 20-80 % time 121ps typ, 155ps min, 104ps max; typ from 2.41 V to 0 V
|   falling waveform, R_fixture 50, V_fixture 3.3: 20-80 % time 137ps typ, 233ps min, 88.9ps max; typ from 3.3 V to 0.845 V
[Pulldown]
-2.61V    -3.409A    -2.716A    -4.462A
-1.199V   -680.7mA   -686.8mA   -732.6mA
-865.9mV  -140.8mA   -251.5mA   -91.59mA
-532.4mV  -37.67mA   -27.84mA   -47.92mA
3.727V    74mA       112.5mA    100.7mA
3.776V    74.12mA    307mA      100.8mA
3.818V    74.29mA    883.2mA    100.9mA
3.957V    76.42mA    9.961A     101.5mA
4.061V    125.5mA    10A        102.9mA
4.11V     388.6mA    10A        103.8mA
4.248V    10A        10A        108.2mA
4.262V    10A        10A        109.3mA
[Pullup]
-962.4mV  10A        10A        3.468A
-948.5mV  10A        10A        2.078A
-892.9mV  4.863A     10A        236.9mA
-858.2mV  1.851A     10A        106.6mA
-823.4mV  578.6mA    10A        80.37mA
-760.9mV  102.5mA    5.267A     70.19mA
-726.1mV  64.45mA    2.651A     67mA
-698.3mV  54.26mA    1.31A      64.55mA
-580.2mV  41.66mA    74.14mA    54.09mA
3.686V    -76.22mA   -58.07mA   -104.8mA
4.326V    -441.6mA   -723.8mA   -135mA
5.91V     -3.49A     -3.011A    -4.128A
[Ramp]
dV/dt_r 1.448/92.133p 1.177/146.688p 1.655/63.885p
dV/dt_f 1.473/136.637p 1.19/233.06p 1.669/88.946p
[Rising Waveform]
R_fixture = 50
V_fixture = 0.
0s        514.3nV    829.9nV    0V
380ps     -72.22mV   -16.65mV   -30.18mV
435ps     -46.82mV   -40.63mV   580.9mV
505ps     46.06mV    -69.38mV   2.331V
595ps     1.188V     -33.37mV   2.708V
640ps     1.887V     -34.35mV   2.742V
700ps     2.26V      13.25mV    2.755V
915ps     2.41V      1.509V     2.758V
1.015ns   2.412V     1.858V     2.758V
2.115ns   2.413V     1.961V     2.758V
[Rising Waveform]
R_fixture = 50
V_fixture = 3.3
V_fixture_min = 3.135
V_fixture_max = 3.465
0s        845.1mV    1.152V     682.8mV
230ps     841.1mV    1.152V     737.3mV
250ps     847mV      1.151V     968.8mV
290ps     953.2mV    1.146V     2.027V
325ps     1.463V     1.144V     2.721V
390ps     2.643V     1.25V      3.179V
485ps     3.108V     2.305V     3.382V
560ps     3.183V     2.862V     3.439V
660ps     3.256V     3.038V     3.463V
2.115ns   3.3V       3.135V     3.465V
[Falling Waveform]
R_fixture = 50
V_fixture = 0.
0s        2.413V     1.961V     2.758V
265ps     2.417V     1.963V     2.699V
290ps     2.388V     1.966V     2.493V
335ps     2.157V     1.962V     1.726V
405ps     1.275V     1.803V     617.3mV
455ps     667mV      1.481V     243.1mV
505ps     334.2mV    1.06V      47.32mV
610ps     55.17mV    338.4mV    9.261mV
750ps     9.81mV     73.13mV    2.4mV
2.115ns   27.36uV    31.28uV    27.88uV
[Falling Waveform]
R_fixture = 50
V_fixture = 3.3
V_fixture_min = 3.135
V_fixture_max = 3.465
0s        3.3V       3.135V     3.465V
430ps     3.392V     3.189V     3.563V
485ps     3.413V     3.201V     3.039V
595ps     3.058V     3.216V     1.074V
680ps     2.068V     3.219V     758mV
760ps     1.311V     3.126V     708.7mV
825ps     1.025V     2.886V     694.2mV
1.025ns   869.6mV    1.77V      684.3mV
1.185ns   851.7mV    1.324V     683.2mV
2.115ns   845.2mV    1.153V     682.9mV
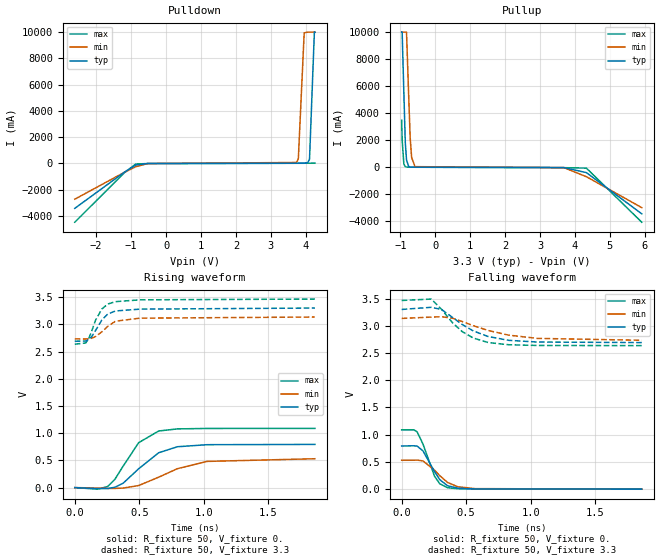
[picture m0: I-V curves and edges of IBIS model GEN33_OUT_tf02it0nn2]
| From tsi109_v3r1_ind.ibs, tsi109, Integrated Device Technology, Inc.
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|   MODEL GEN33_OUT_tf02it0nn2
[Model]   GEN33_OUT_tf02it0nn2
Model_type  Output
C_comp 1.269p 1.184p 1.348p
Polarity   Non-Inverting
Enable   Active-High
Vmeas =   1.65V
|   typ   min   max
[Model Spec]
[Temperature Range]   25   125   -40
[Voltage Range] 3.3 3.135 3.465
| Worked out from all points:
|   slope of the pulldown table from 0 to 0.495 V, typ, clamps not added: 80.9 ohm
|   slope of the pullup table from 0 to 0.495 V, typ, clamps not added: 76.1 ohm
|   rising waveform, R_fixture 50, V_fixture 0.: 20-80 % time 230ps typ, 323ps min, 184ps max; typ from 0 V to 0.794 V
|   rising waveform, R_fixture 50, V_fixture 3.3: 20-80 % time 107ps typ, 127ps min, 95.7ps max; typ from 2.69 V to 3.3 V
|   falling waveform, R_fixture 50, V_fixture 0.: 20-80 % time 118ps typ, 144ps min, 101ps max; typ from 0.794 V to 0 V
|   falling waveform, R_fixture 50, V_fixture 3.3: 20-80 % time 275ps typ, 373ps min, 221ps max; typ from 3.3 V to 2.69 V
[Pulldown]
-2.615V   -3.418A    -2.722A    -4.473A
-1.189V   -657.4mA   -670.6mA   -696.4mA
-869.3mV  -121.4mA   -251.1mA   -44.73mA
-528.5mV  -7.498mA   -8.285mA   -9.997mA
3.727V    12.4mA     72.18mA    16.89mA
3.762V    12.44mA    182.2mA    16.9mA
3.79V     12.5mA     393.1mA    16.92mA
3.957V    14.56mA    9.941A     17.28mA
4.061V    64.24mA    10A        18.42mA
4.11V     331mA      10A        19.27mA
4.249V    10A        10A        23.25mA
4.263V    10A        10A        24.35mA
[Pullup]
-962.9mV  10A        10A        3.482A
-949mV    10A        10A        2.069A
-900.3mV  5.546A     10A        249mA
-858.6mV  1.837A     10A        51.79mA
-823.8mV  545.2mA    10A        26.36mA
-761.2mV  62.8mA     5.27A      18.88mA
-719.5mV  22.48mA    2.226A     17.13mA
-677.8mV  13.52mA    735.8mA    15.61mA
-580.4mV  9.367mA    51.69mA    12.46mA
3.682V    -16.34mA   -17.56mA   -22.46mA
4.329V    -387.2mA   -688.2mA   -54.17mA
5.915V    -3.435A    -2.975A    -4.052A
[Ramp]
dV/dt_r .476/230.063p .318/323.059p .653/183.508p
dV/dt_f .365/274.969p .241/374.442p .498/220.766p
[Rising Waveform]
R_fixture = 50
V_fixture = 0.
0s        0V         0V         0V
175ps     -18.58mV   -7.316mV   -28.75mV
255ps     -17.18mV   -15.31mV   20.26mV
310ps     5.743mV    -15.55mV   149.1mV
375ps     81.29mV    -8.553mV   395.9mV
495ps     346.3mV    37.75mV    825.6mV
650ps     640.6mV    191.6mV    1.04V
795ps     750.9mV    347.9mV    1.079V
1.025ns   788.5mV    481.4mV    1.087V
1.86ns    793.7mV    530.4mV    1.088V
[Rising Waveform]
R_fixture = 50
V_fixture = 3.3
V_fixture_min = 3.135
V_fixture_max = 3.465
0s        2.691V     2.733V     2.636V
85ps      2.693V     2.731V     2.658V
110ps     2.725V     2.734V     2.751V
130ps     2.771V     2.745V     2.866V
160ps     2.883V     2.775V     3.072V
210ps     3.081V     2.863V     3.283V
255ps     3.189V     2.963V     3.373V
315ps     3.246V     3.058V     3.417V
505ps     3.28V      3.114V     3.451V
1.86ns    3.3V       3.135V     3.465V
[Falling Waveform]
R_fixture = 50
V_fixture = 0.
0s        793.7mV    530.7mV    1.088V
95ps      796mV      531.3mV    1.089V
120ps     790.8mV    533.9mV    1.052V
165ps     703.5mV    518.9mV    829.5mV
255ps     321.5mV    348.6mV    236.4mV
295ps     175.3mV    248.6mV    99.82mV
355ps     63.82mV    124mV      26.66mV
435ps     17.77mV    43.75mV    7.837mV
570ps     4.592mV    9.819mV    2.576mV
1.86ns    2.98uV     32.28uV    894.2nV
[Falling Waveform]
R_fixture = 50
V_fixture = 3.3
V_fixture_min = 3.135
V_fixture_max = 3.465
0s        3.3V       3.135V     3.465V
230ps     3.34V      3.16V      3.491V
310ps     3.298V     3.166V     3.3V
395ps     3.152V     3.139V     3.053V
470ps     3.023V     3.078V     2.892V
555ps     2.906V     3.002V     2.775V
670ps     2.803V     2.914V     2.693V
830ps     2.733V     2.828V     2.652V
1.05ns    2.702V     2.769V     2.639V
1.86ns    2.692V     2.734V     2.636V
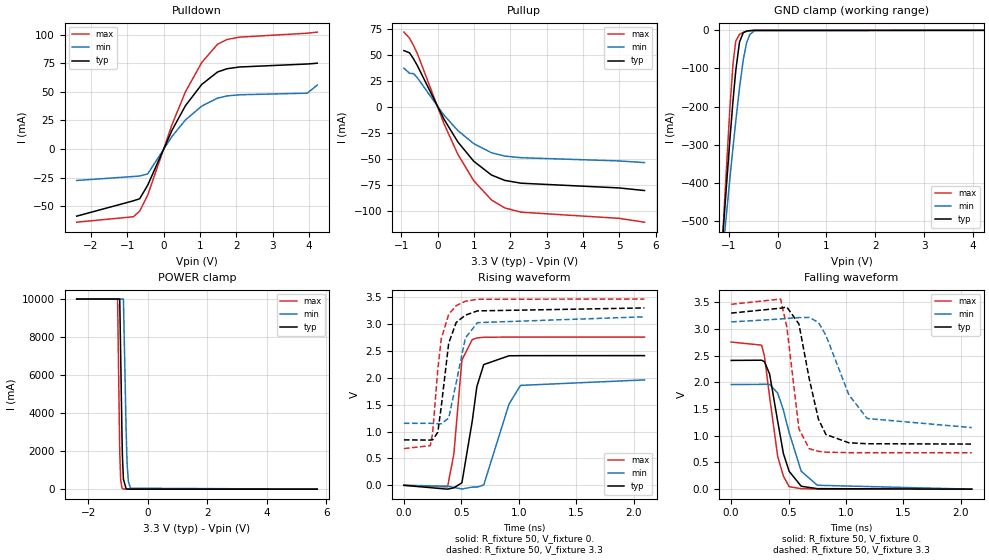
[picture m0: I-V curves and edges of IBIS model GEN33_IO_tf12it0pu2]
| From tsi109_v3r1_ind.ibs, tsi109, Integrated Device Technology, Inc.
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|   MODEL GEN33_IO_tf12it0pu2
[Model]   GEN33_IO_tf12it0pu2
Model_type  I/O
C_comp 1.241p 1.146p 1.337p
Polarity   Non-Inverting
Enable   Active-High
|   typ   min   max
Vinl   =   0.800v
Vinh   =   2.000v
Vmeas  =   1.65V
[Model Spec]
[Temperature Range]   25   125   -40
[Voltage Range] 3.3 3.135 3.465
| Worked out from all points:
|   slope of the pulldown table from 0 to 0.495 V, typ, clamps not added: 15.2 ohm
|   slope of the pullup table from 0 to 0.495 V, typ, clamps not added: 16.3 ohm
|   GND clamp passes 1 mA (typ) near -0.60 V on its own axis
|   POWER clamp passes 1 mA (typ) near -0.62 V on its own axis
|   rising waveform, R_fixture 50, V_fixture 0.: 20-80 % time 92.3ps typ, 147ps min, 63.9ps max; typ from 0 V to 2.41 V
|   rising waveform, R_fixture 50, V_fixture 3.3: 20-80 % time 89.9ps typ, 107ps min, 82.1ps max; typ from 0.845 V to 3.3 V
|   falling waveform, R_fixture 50, V_fixture 0.: 20-80 % time 121ps typ, 155ps min, 104ps max; typ from 2.41 V to 0 V
|   falling waveform, R_fixture 50, V_fixture 3.3: 20-80 % time 137ps typ, 233ps min, 89ps max; typ from 3.3 V to 0.845 V
[Pulldown]
-2.396V   -58.71mA   -27.53mA   -64mA
-836.4mV  -45.32mA   -24.04mA   -59.24mA
-662.3mV  -43.5mA    -23.65mA   -54.36mA
-441.4mV  -31.66mA   -21.77mA   -40.36mA
227.9mV   16.37mA    11.04mA    21.32mA
596.1mV   37.81mA    25.33mA    49.91mA
1.045V    56.42mA    37.49mA    75.67mA
1.48V     67.31mA    44.47mA    91.56mA
1.741V    70.16mA    46.38mA    95.74mA
2.089V    71.69mA    47.39mA    97.8mA
3.95V     74.3mA     48.8mA     101.2mA
4.224V    74.99mA    55.83mA    102.2mA
[Pullup]
-924.1mV  53.85mA    37.04mA    71.64mA
-770.1mV  51.75mA    32.07mA    65.88mA
-656.3mV  45.76mA    31.75mA    58.52mA
-549.2mV  39.1mA     27.58mA    50.6mA
173.7mV   -11.72mA   -7.927mA   -15.86mA
561.9mV   -33.85mA   -22.93mA   -45.82mA
997mV     -52.31mA   -35.41mA   -70.97mA
1.486V    -65.55mA   -44.2mA    -89.46mA
1.854V    -70.72mA   -47.4mA    -97.14mA
2.302V    -73.39mA   -48.92mA   -101.2mA
4.993V    -77.91mA   -52mA      -107.1mA
5.696V    -80.41mA   -53.59mA   -110.8mA
[GND Clamp]
-2.396V   -2.986A    -2.401A    -3.883A
-1.125V   -539.1mA   -582mA     -536mA
-1.08V    -460.1mA   -522.3mA   -429.8mA
-980.8mV  -288.7mA   -390.7mA   -206.8mA
-914.5mV  -183.2mA   -306mA     -86.21mA
-859.2mV  -105.7mA   -238.3mA   -28.4mA
-781.8mV  -30.47mA   -150.3mA   -10.18mA
-704.4mV  -5.865mA   -76.54mA   -5.768mA
-638.1mV  -1.88mA    -33.14mA   -3.043mA
-571.7mV  -653.7uA   -10.9mA    -1.204mA
-472.2mV  -101.4uA   -1.108mA   -163.5uA
4.224V    0A         0A         0A
[Power Clamp]
-2.396V   10A        10A        10A
-1.02V    10A        10A        10A
-947.9mV  10A        10A        1.97A
-914.4mV  6.902A     10A        449.6mA
-871.2mV  2.745A     10A        61.86mA
-856.8mV  1.723A     10A        33.78mA
-823.3mV  523.1mA    10A        11.34mA
-732.2mV  18.06mA    3.036A     4.016mA
-698.6mV  6.162mA    1.286A     3.214mA
-655.4mV  2.061mA    389.7mA    2.329mA
-583.5mV  591.4uA    49.53mA    1.147mA
5.696V    0A         0A         0A
[Ramp]
dV/dt_r 1.448/92.335p 1.177/146.677p 1.655/63.892p
dV/dt_f 1.473/136.643p 1.189/233.099p 1.669/88.994p
[Rising Waveform]
R_fixture = 50
V_fixture = 0.
0s        116.3uV    107.9uV    129.9uV
380ps     -71.76mV   -16.54mV   -29.29mV
435ps     -46.21mV   -40.5mV    582mV
505ps     46.72mV    -69.1mV    2.332V
595ps     1.195V     -32.96mV   2.711V
635ps     1.835V     -33.72mV   2.741V
695ps     2.246V     4.675mV    2.754V
915ps     2.41V      1.51V      2.758V
1.015ns   2.412V     1.859V     2.758V
2.095ns   2.413V     1.961V     2.758V
[Rising Waveform]
R_fixture = 50
V_fixture = 3.3
V_fixture_min = 3.135
V_fixture_max = 3.465
0s        845.3mV    1.153V     683.1mV
230ps     841.3mV    1.153V     737.6mV
250ps     847.2mV    1.151V     969.3mV
295ps     985.8mV    1.146V     2.155V
325ps     1.463V     1.144V     2.723V
390ps     2.644V     1.251V     3.181V
455ps     3.029V     1.906V     3.343V
535ps     3.165V     2.741V     3.424V
640ps     3.245V     3.026V     3.462V
2.095ns   3.3V       3.135V     3.465V
[Falling Waveform]
R_fixture = 50
V_fixture = 0.
0s        2.413V     1.961V     2.758V
265ps     2.417V     1.964V     2.699V
290ps     2.389V     1.967V     2.493V
335ps     2.157V     1.962V     1.726V
405ps     1.275V     1.802V     617.4mV
455ps     667mV      1.481V     243.3mV
505ps     334.4mV    1.06V      47.46mV
610ps     55.36mV    338.2mV    9.333mV
750ps     9.895mV    73.37mV    2.473mV
2.095ns   119uV      123.7uV    131.5uV
[Falling Waveform]
R_fixture = 50
V_fixture = 3.3
V_fixture_min = 3.135
V_fixture_max = 3.465
0s        3.3V       3.135V     3.465V
430ps     3.392V     3.189V     3.563V
485ps     3.413V     3.201V     3.039V
590ps     3.096V     3.215V     1.131V
680ps     2.068V     3.219V     758mV
760ps     1.312V     3.126V     708.7mV
825ps     1.025V     2.885V     694.2mV
1.025ns   869.7mV    1.769V     684.3mV
1.185ns   851.7mV    1.324V     683.3mV
2.095ns   845.4mV    1.154V     683.1mV
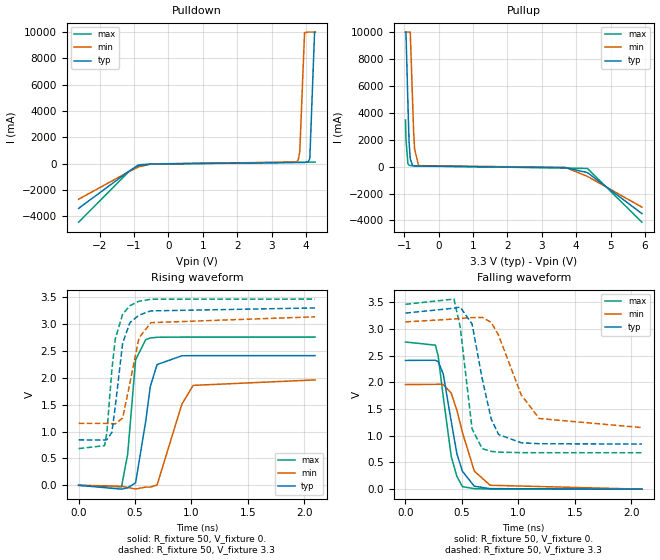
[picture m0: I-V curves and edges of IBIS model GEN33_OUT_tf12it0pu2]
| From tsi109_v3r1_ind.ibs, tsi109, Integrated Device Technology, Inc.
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|   MODEL GEN33_OUT_tf12it0pu2
[Model]   GEN33_OUT_tf12it0pu2
Model_type  Output
C_comp 1.76p 1.71p 1.799p
Polarity   Non-Inverting
Enable   Active-High
Vmeas =   1.65V
|   typ   min   max
[Model Spec]
[Temperature Range]   25   125   -40
[Voltage Range] 3.3 3.135 3.465
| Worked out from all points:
|   slope of the pulldown table from 0 to 0.495 V, typ, clamps not added: 15.5 ohm
|   slope of the pullup table from 0 to 0.495 V, typ, clamps not added: 16.3 ohm
|   rising waveform, R_fixture 50, V_fixture 0.: 20-80 % time 92.3ps typ, 147ps min, 63.9ps max; typ from 0 V to 2.41 V
|   rising waveform, R_fixture 50, V_fixture 3.3: 20-80 % time 89.9ps typ, 107ps min, 82.1ps max; typ from 0.845 V to 3.3 V
|   falling waveform, R_fixture 50, V_fixture 0.: 20-80 % time 121ps typ, 155ps min, 104ps max; typ from 2.41 V to 0 V
|   falling waveform, R_fixture 50, V_fixture 3.3: 20-80 % time 137ps typ, 233ps min, 89ps max; typ from 3.3 V to 0.845 V
[Pulldown]
-2.61V    -3.409A    -2.716A    -4.462A
-1.137V   -567.6mA   -601.5mA   -583.8mA
-865.9mV  -140.8mA   -251.5mA   -91.6mA
-490.7mV  -34.96mA   -24.95mA   -44.54mA
3.727V    74mA       112.5mA    100.7mA
3.776V    74.13mA    307mA      100.8mA
3.818V    74.29mA    883.2mA    100.9mA
3.957V    76.42mA    9.961A     101.5mA
4.061V    125.5mA    10A        102.9mA
4.11V     388.6mA    10A        103.9mA
4.248V    10A        10A        108.2mA
4.262V    10A        10A        109.3mA
[Pullup]
-962.4mV  10A        10A        3.468A
-948.5mV  10A        10A        2.078A
-892.9mV  4.863A     10A        236.9mA
-858.2mV  1.851A     10A        106.6mA
-823.4mV  578.6mA    10A        80.38mA
-760.9mV  102.5mA    5.267A     70.2mA
-726.1mV  64.46mA    2.651A     67.01mA
-698.3mV  54.26mA    1.31A      64.56mA
-580.2mV  41.67mA    74.14mA    54.1mA
3.686V    -76.24mA   -58.07mA   -104.8mA
4.326V    -441.6mA   -723.8mA   -135mA
5.91V     -3.49A     -3.011A    -4.128A
[Ramp]
dV/dt_r 1.448/92.339p 1.177/146.677p 1.655/63.888p
dV/dt_f 1.473/136.641p 1.189/233.088p 1.669/88.997p
[Rising Waveform]
R_fixture = 50
V_fixture = 0.
0s        116.3uV    107.9uV    129.9uV
380ps     -71.76mV   -16.54mV   -29.29mV
435ps     -46.21mV   -40.5mV    582mV
505ps     46.72mV    -69.1mV    2.332V
595ps     1.195V     -32.96mV   2.711V
635ps     1.835V     -33.72mV   2.741V
695ps     2.246V     4.675mV    2.754V
915ps     2.41V      1.51V      2.758V
1.015ns   2.412V     1.859V     2.758V
2.095ns   2.413V     1.961V     2.758V
[Rising Waveform]
R_fixture = 50
V_fixture = 3.3
V_fixture_min = 3.135
V_fixture_max = 3.465
0s        845.3mV    1.153V     683.1mV
230ps     841.3mV    1.153V     737.6mV
250ps     847.2mV    1.151V     969.3mV
295ps     985.8mV    1.146V     2.155V
325ps     1.463V     1.144V     2.723V
390ps     2.644V     1.251V     3.181V
455ps     3.029V     1.906V     3.343V
535ps     3.165V     2.741V     3.424V
640ps     3.245V     3.026V     3.462V
2.095ns   3.3V       3.135V     3.465V
[Falling Waveform]
R_fixture = 50
V_fixture = 0.
0s        2.413V     1.961V     2.758V
265ps     2.417V     1.964V     2.699V
290ps     2.389V     1.967V     2.493V
335ps     2.157V     1.962V     1.726V
405ps     1.275V     1.802V     617.4mV
455ps     667mV      1.481V     243.3mV
505ps     334.4mV    1.06V      47.46mV
610ps     55.36mV    338.2mV    9.333mV
750ps     9.894mV    73.38mV    2.473mV
2.095ns   119uV      123.7uV    131.5uV
[Falling Waveform]
R_fixture = 50
V_fixture = 3.3
V_fixture_min = 3.135
V_fixture_max = 3.465
0s        3.3V       3.135V     3.465V
430ps     3.392V     3.189V     3.563V
485ps     3.413V     3.201V     3.039V
590ps     3.096V     3.215V     1.131V
680ps     2.068V     3.219V     758mV
760ps     1.312V     3.126V     708.7mV
825ps     1.025V     2.885V     694.2mV
1.025ns   869.7mV    1.769V     684.3mV
1.185ns   851.7mV    1.324V     683.3mV
2.095ns   845.4mV    1.154V     683.1mV
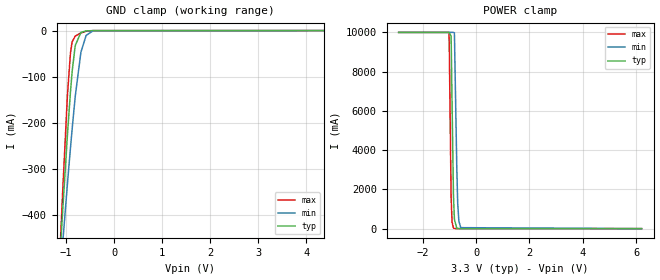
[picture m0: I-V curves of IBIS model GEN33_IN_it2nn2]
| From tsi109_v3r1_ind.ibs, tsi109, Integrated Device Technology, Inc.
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|   MODEL GEN33_IN_it2nn2
[Model]   GEN33_IN_it2nn2
Model_type  Input
C_comp 2.394p 2.212p 2.584p
Polarity   Non-Inverting
Enable   Active-High
|   typ   min   max
Vinl   =   0.800v
Vinh   =   2.000v
[Model Spec]
[Temperature Range]   25   125   -40
[Voltage Range] 3.3 3.135 3.465
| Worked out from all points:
|   GND clamp passes 1 mA (typ) near -0.60 V on its own axis
|   POWER clamp passes 1 mA (typ) near -0.61 V on its own axis
[GND Clamp]
-2.907V   -3.934A    -3.096A    -5.193A
-1.128V   -490mA     -536.5mA   -481mA
-1.11V    -457.8mA   -512.1mA   -437.7mA
-1.073V   -394.2mA   -463.8mA   -352.9mA
-973.5mV  -227.7mA   -334.2mA   -141.8mA
-910mV    -133.6mA   -255.6mA   -48.98mA
-873.7mV  -87.95mA   -212.7mA   -24.12mA
-810.2mV  -32.55mA   -143mA     -11.87mA
-692.2mV  -3.96mA    -47.09mA   -5.192mA
-583.3mV  -769.3uA   -10.53mA   -1.437mA
-438.1mV  -39.28uA   -361.9uA   -59.58uA
4.367V    0A         0A         0A
[Power Clamp]
-2.907V   10A        10A        10A
-1.019V   10A        10A        10A
-1.01V    10A        10A        9.43A
-939.5mV  9.811A     10A        1.625A
-904.3mV  6.385A     10A        333.4mA
-851.3mV  1.685A     10A        31.27mA
-816.1mV  479.8mA    9.979A     10.35mA
-727.8mV  18.31mA    3.205A     3.903mA
-692.6mV  5.866mA    1.305A     3.074mA
-648.5mV  1.899mA    385.4mA    2.189mA
-577.9mV  540uA      50.95mA    1.062mA
6.207V    0A         0A         0A
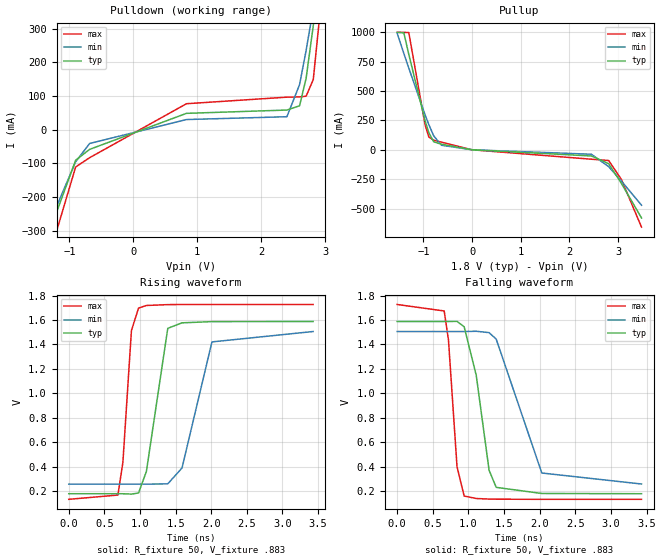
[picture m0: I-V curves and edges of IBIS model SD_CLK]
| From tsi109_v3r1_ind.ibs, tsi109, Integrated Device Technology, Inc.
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|   MODEL SD_CLK
[Model]   SD_CLK
Model_type  Output
Polarity   Non-Inverting
Enable   Active-High
|   typ   min   max
C_comp 3.3p 3.146p 3.473p
Cref  = 20pF
Vmeas = 0.9v
[Model Spec]
[Temperature Range]   25   125   -40
[Voltage Range] 1.8 1.79 1.89
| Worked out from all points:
|   slope of the pulldown table from 0 to 0.27 V, typ, clamps not added: 13.3 ohm
|   slope of the pullup table from 0 to 0.27 V, typ, clamps not added: 15.4 ohm
|   rising waveform, R_fixture 50, V_fixture .883: 20-80 % time 155ps typ, 240ps min, 101ps max; typ from 0.179 V to 1.59 V
|   falling waveform, R_fixture 50, V_fixture .883: 20-80 % time 210ps typ, 386ps min, 109ps max; typ from 1.59 V to 0.179 V
[Pulldown]
-1.684V   -581.6mA   -466.6mA   -753.6mA
-1.201V   -245.3mA   -228.4mA   -301.6mA
-901.5mV  -90.52mA   -95.12mA   -110.5mA
-683.1mV  -58.2mA    -40.72mA   -82.88mA
830.6mV   48.59mA    30.21mA    77.11mA
2.4V      58.36mA    38.59mA    96.56mA
2.598V    71.03mA    134mA      97.37mA
2.7V      152.4mA    234.9mA    99.38mA
2.812V    308.6mA    359.5mA    148.7mA
2.949V    538.4mA    521.3mA    405.6mA
3.192V    978.1mA    820.1mA    997.4mA
3.34V     1A         1A         1A
[Pullup]
-1.54V    1A         991.8mA    1A
-1.403V   995.8mA    820.5mA    1A
-1.301V   812mA      694.9mA    997.8mA
-965.8mV  246.7mA    297.1mA    211.6mA
-889.6mV  146mA      214.7mA    108.8mA
-788mV    67.71mA    117.9mA    81.5mA
-630.6mV  47.48mA    38.48mA    65.21mA
331.6uV   -8.022uA   0A         -18.6uA
2.453V    -52.77mA   -38.02mA   -80.31mA
2.808V    -118.4mA   -143.5mA   -91.28mA
3.067V    -284.1mA   -265.1mA   -250.3mA
3.484V    -580.9mA   -471.9mA   -658.7mA
[Ramp]
dV/dt_r .845/154.678p .749/240.064p .956/101.167p
dV/dt_f .845/210.589p .749/385.819p .956/108.694p
[Rising Waveform]
R_fixture = 50
V_fixture = .883
V_fixture_min = .882
V_fixture_max = .93
0s        179.2mV    257.7mV    133.3mV
690ps     179.3mV    257.7mV    168.3mV
760ps     179mV      257.7mV    435.5mV
880ps     176.2mV    257.8mV    1.514V
980ps     185.4mV    257.7mV    1.698V
1.09ns    361.5mV    257.5mV    1.719V
1.39ns    1.532V     259.8mV    1.726V
1.59ns    1.577V     389.7mV    1.727V
2.01ns    1.587V     1.421V     1.727V
3.43ns    1.588V     1.506V     1.727V
[Falling Waveform]
R_fixture = 50
V_fixture = .883
V_fixture_min = .882
V_fixture_max = .93
0s        1.588V     1.506V     1.727V
660ps     1.588V     1.506V     1.674V
720ps     1.588V     1.506V     1.437V
840ps     1.589V     1.506V     399.9mV
940ps     1.545V     1.506V     160.3mV
1.11ns    1.147V     1.508V     140mV
1.29ns    371.6mV    1.497V     135.5mV
1.39ns    231.1mV    1.444V     134.5mV
2.03ns    181.2mV    348.6mV    133.3mV
3.43ns    179.2mV    258.6mV    133.3mV
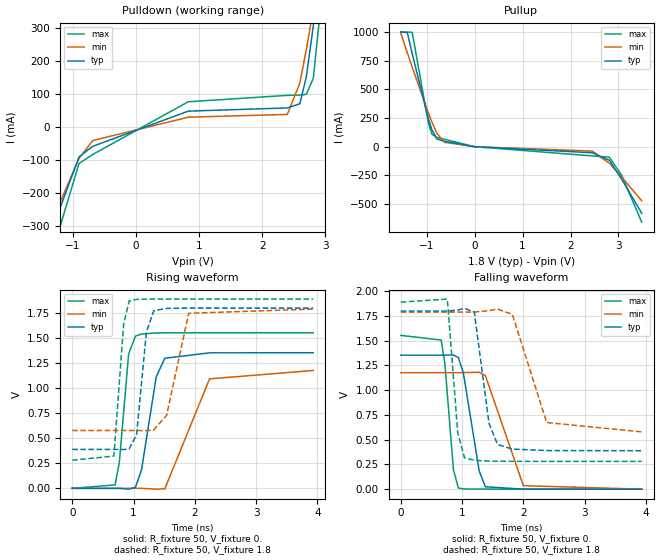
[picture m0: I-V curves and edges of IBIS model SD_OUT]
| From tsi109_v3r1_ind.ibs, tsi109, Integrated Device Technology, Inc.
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|   MODEL SD_OUT
[Model]   SD_OUT
Model_type  Output
Polarity   Non-Inverting
Enable   Active-High
|   typ   min   max
C_comp 2.84p 2.652p 2.982p
Cref  = 20pF
Vmeas = 0.9v
[Model Spec]
[Temperature Range]   25   125   -40
[Voltage Range] 1.8 1.79 1.89
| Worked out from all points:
|   slope of the pulldown table from 0 to 0.27 V, typ, clamps not added: 13.3 ohm
|   slope of the pullup table from 0 to 0.27 V, typ, clamps not added: 15.4 ohm
|   rising waveform, R_fixture 50, V_fixture 0.: 20-80 % time 205ps typ, 349ps min, 124ps max; typ from 0 V to 1.35 V
|   rising waveform, R_fixture 50, V_fixture 1.8: 20-80 % time 121ps typ, 175ps min, 85.3ps max; typ from 0.389 V to 1.8 V
|   falling waveform, R_fixture 50, V_fixture 0.: 20-80 % time 211ps typ, 322ps min, 119ps max; typ from 1.35 V to 0 V
|   falling waveform, R_fixture 50, V_fixture 1.8: 20-80 % time 164ps typ, 287ps min, 100ps max; typ from 1.8 V to 0.389 V
[Pulldown]
-1.684V   -581.6mA   -466.6mA   -753.6mA
-1.201V   -245.3mA   -228.4mA   -301.6mA
-901.5mV  -90.52mA   -95.12mA   -110.5mA
-683.1mV  -58.2mA    -40.72mA   -82.88mA
830.6mV   48.59mA    30.21mA    77.11mA
2.4V      58.36mA    38.59mA    96.56mA
2.598V    71.03mA    134mA      97.37mA
2.7V      152.4mA    234.9mA    99.38mA
2.812V    308.6mA    359.5mA    148.7mA
2.949V    538.4mA    521.3mA    405.6mA
3.192V    978.1mA    820.1mA    997.4mA
3.34V     1A         1A         1A
[Pullup]
-1.54V    1A         991.8mA    1A
-1.403V   995.8mA    820.5mA    1A
-1.301V   812mA      694.9mA    997.8mA
-965.8mV  246.7mA    297.1mA    211.6mA
-889.6mV  146mA      214.7mA    108.8mA
-788mV    67.71mA    117.9mA    81.5mA
-630.6mV  47.48mA    38.48mA    65.21mA
331.6uV   -8.022uA   0A         -18.6uA
2.453V    -52.77mA   -38.02mA   -80.31mA
2.808V    -118.4mA   -143.5mA   -91.28mA
3.067V    -284.1mA   -265.1mA   -250.3mA
3.484V    -580.9mA   -471.9mA   -658.7mA
[Ramp]
dV/dt_r .812/205.301p .707/348.99p .932/123.841p
dV/dt_f .847/164.059p .727/287.544p .965/99.224p
[Rising Waveform]
R_fixture = 50
V_fixture = 0.
0s        0V         0V         0V
700ps     244.7uV    -162.2nV   34.43mV
770ps     45.99uV    15.38uV    266.2mV
920ps     -8.22mV    145.7uV    1.341V
1.03ns    8.816mV    242.4uV    1.519V
1.13ns    183mV      148.2uV    1.541V
1.37ns    1.113V     -7.905mV   1.552V
1.51ns    1.299V     -5.149mV   1.553V
2.24ns    1.353V     1.093V     1.554V
3.93ns    1.354V     1.177V     1.554V
[Rising Waveform]
R_fixture = 50
V_fixture = 1.8
V_fixture_min = 1.79
V_fixture_max = 1.89
0s        388.5mV    577.9mV    281mV
680ps     388.4mV    577.9mV    322.1mV
840ps     387.5mV    577.9mV    1.646V
930ps     394.5mV    577.9mV    1.871V
1.05ns    536.2mV    577.3mV    1.887V
1.21ns    1.561V     576.6mV    1.889V
1.33ns    1.773V     582.6mV    1.89V
1.54ns    1.797V     730.6mV    1.89V
1.9ns     1.8V       1.748V     1.89V
3.93ns    1.8V       1.79V      1.89V
[Falling Waveform]
R_fixture = 50
V_fixture = 0.
0s        1.354V     1.177V     1.554V
660ps     1.354V     1.177V     1.507V
720ps     1.355V     1.177V     1.268V
860ps     1.356V     1.177V     195.7mV
940ps     1.33V      1.177V     11.99mV
1.02ns    1.179V     1.178V     2.701mV
1.28ns    184.2mV    1.181V     560.7uV
1.38ns    24.12mV    1.149V     304.9uV
2ns       345.6uV    35.33mV    11.37uV
3.93ns    -549.9nV   23.54uV    0V
[Falling Waveform]
R_fixture = 50
V_fixture = 1.8
V_fixture_min = 1.79
V_fixture_max = 1.89
0s        1.8V       1.79V      1.89V
760ps     1.8V       1.79V      1.921V
930ps     1.81V      1.79V      568.7mV
1.04ns    1.828V     1.79V      317.3mV
1.2ns     1.789V     1.79V      291.7mV
1.44ns    663.4mV    1.804V     283.6mV
1.58ns    451.5mV    1.819V     282.2mV
1.82ns    405.1mV    1.767V     281.3mV
2.38ns    390.2mV    673.5mV    281mV
3.93ns    388.5mV    578.8mV    281mV
